VERSION 5.7 ;
  NOWIREEXTENSIONATPIN ON ;
  DIVIDERCHAR "/" ;
  BUSBITCHARS "[]" ;
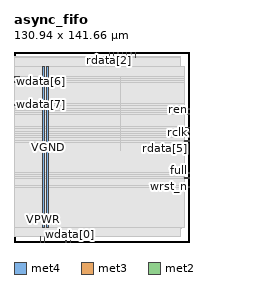
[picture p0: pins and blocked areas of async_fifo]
MACRO async_fifo
  CLASS BLOCK ;
  FOREIGN async_fifo ;
  ORIGIN 0.000 0.000 ;
  SIZE 130.940 BY 141.660 ;
  PIN VGND
    DIRECTION INOUT ;
    USE GROUND ;
    PORT
      LAYER met4 ;
        RECT 24.340 10.640 25.940 130.800 ;
    END
  END VGND
  PIN VPWR
    DIRECTION INOUT ;
    USE POWER ;
    PORT
      LAYER met4 ;
        RECT 21.040 10.640 22.640 130.800 ;
    END
  END VPWR
  PIN empty
    DIRECTION OUTPUT ;
    USE SIGNAL ;
    ANTENNADIFFAREA 0.340600 ;
    PORT
      LAYER met3 ;
        RECT 126.940 95.240 130.940 95.840 ;
    END
  END empty
  PIN full
    DIRECTION OUTPUT ;
    USE SIGNAL ;
    ANTENNADIFFAREA 0.340600 ;
    PORT
      LAYER met3 ;
        RECT 126.940 47.640 130.940 48.240 ;
    END
  END full
  PIN rclk
    DIRECTION INPUT ;
    USE SIGNAL ;
    ANTENNAGATEAREA 0.852000 ;
    PORT
      LAYER met3 ;
        RECT 126.940 81.640 130.940 82.240 ;
    END
  END rclk
  PIN rdata[0]
    DIRECTION OUTPUT ;
    USE SIGNAL ;
    ANTENNADIFFAREA 0.340600 ;
    PORT
      LAYER met3 ;
        RECT 126.940 78.240 130.940 78.840 ;
    END
  END rdata[0]
  PIN rdata[1]
    DIRECTION OUTPUT ;
    USE SIGNAL ;
    ANTENNADIFFAREA 0.340600 ;
    PORT
      LAYER met2 ;
        RECT 87.030 137.660 87.310 141.660 ;
    END
  END rdata[1]
  PIN rdata[2]
    DIRECTION OUTPUT ;
    USE SIGNAL ;
    ANTENNADIFFAREA 0.340600 ;
    PORT
      LAYER met2 ;
        RECT 70.930 137.660 71.210 141.660 ;
    END
  END rdata[2]
  PIN rdata[3]
    DIRECTION OUTPUT ;
    USE SIGNAL ;
    ANTENNADIFFAREA 0.340600 ;
    PORT
      LAYER met2 ;
        RECT 74.150 137.660 74.430 141.660 ;
    END
  END rdata[3]
  PIN rdata[4]
    DIRECTION OUTPUT ;
    USE SIGNAL ;
    ANTENNADIFFAREA 0.340600 ;
    PORT
      LAYER met2 ;
        RECT 80.590 137.660 80.870 141.660 ;
    END
  END rdata[4]
  PIN rdata[5]
    DIRECTION OUTPUT ;
    USE SIGNAL ;
    ANTENNADIFFAREA 0.340600 ;
    PORT
      LAYER met3 ;
        RECT 126.940 74.840 130.940 75.440 ;
    END
  END rdata[5]
  PIN rdata[6]
    DIRECTION OUTPUT ;
    USE SIGNAL ;
    ANTENNADIFFAREA 0.340600 ;
    PORT
      LAYER met2 ;
        RECT 83.810 137.660 84.090 141.660 ;
    END
  END rdata[6]
  PIN rdata[7]
    DIRECTION OUTPUT ;
    USE SIGNAL ;
    ANTENNADIFFAREA 0.340600 ;
    PORT
      LAYER met2 ;
        RECT 77.370 137.660 77.650 141.660 ;
    END
  END rdata[7]
  PIN ren
    DIRECTION INPUT ;
    USE SIGNAL ;
    ANTENNAGATEAREA 0.196500 ;
    PORT
      LAYER met3 ;
        RECT 126.940 98.640 130.940 99.240 ;
    END
  END ren
  PIN rrst_n
    DIRECTION INPUT ;
    USE SIGNAL ;
    ANTENNAGATEAREA 0.426000 ;
    PORT
      LAYER met3 ;
        RECT 126.940 85.040 130.940 85.640 ;
    END
  END rrst_n
  PIN wclk
    DIRECTION INPUT ;
    USE SIGNAL ;
    ANTENNAGATEAREA 0.852000 ;
    PORT
      LAYER met3 ;
        RECT 0.000 122.440 4.000 123.040 ;
    END
  END wclk
  PIN wdata[0]
    DIRECTION INPUT ;
    USE SIGNAL ;
    ANTENNAGATEAREA 0.213000 ;
    PORT
      LAYER met2 ;
        RECT 41.950 0.000 42.230 4.000 ;
    END
  END wdata[0]
  PIN wdata[1]
    DIRECTION INPUT ;
    USE SIGNAL ;
    ANTENNAGATEAREA 0.213000 ;
    PORT
      LAYER met2 ;
        RECT 90.250 137.660 90.530 141.660 ;
    END
  END wdata[1]
  PIN wdata[2]
    DIRECTION INPUT ;
    USE SIGNAL ;
    ANTENNAGATEAREA 0.213000 ;
    PORT
      LAYER met2 ;
        RECT 22.630 0.000 22.910 4.000 ;
    END
  END wdata[2]
  PIN wdata[3]
    DIRECTION INPUT ;
    USE SIGNAL ;
    ANTENNAGATEAREA 0.213000 ;
    PORT
      LAYER met2 ;
        RECT 61.270 137.660 61.550 141.660 ;
    END
  END wdata[3]
  PIN wdata[4]
    DIRECTION INPUT ;
    USE SIGNAL ;
    ANTENNAGATEAREA 0.213000 ;
    PORT
      LAYER met2 ;
        RECT 38.730 0.000 39.010 4.000 ;
    END
  END wdata[4]
  PIN wdata[5]
    DIRECTION INPUT ;
    USE SIGNAL ;
    ANTENNAGATEAREA 0.213000 ;
    PORT
      LAYER met2 ;
        RECT 19.410 0.000 19.690 4.000 ;
    END
  END wdata[5]
  PIN wdata[6]
    DIRECTION INPUT ;
    USE SIGNAL ;
    ANTENNAGATEAREA 0.213000 ;
    PORT
      LAYER met3 ;
        RECT 0.000 119.040 4.000 119.640 ;
    END
  END wdata[6]
  PIN wdata[7]
    DIRECTION INPUT ;
    USE SIGNAL ;
    ANTENNAGATEAREA 0.213000 ;
    PORT
      LAYER met3 ;
        RECT 0.000 102.040 4.000 102.640 ;
    END
  END wdata[7]
  PIN wen
    DIRECTION INPUT ;
    USE SIGNAL ;
    ANTENNAGATEAREA 0.196500 ;
    PORT
      LAYER met3 ;
        RECT 126.940 51.040 130.940 51.640 ;
    END
  END wen
  PIN wrst_n
    DIRECTION INPUT ;
    USE SIGNAL ;
    ANTENNAGATEAREA 0.426000 ;
    PORT
      LAYER met3 ;
        RECT 126.940 40.840 130.940 41.440 ;
    END
  END wrst_n
  OBS
      LAYER nwell ;
        RECT 5.330 10.795 125.310 130.645 ;
      LAYER li1 ;
        RECT 5.520 10.795 125.120 130.645 ;
      LAYER met1 ;
        RECT 0.530 10.240 125.120 130.800 ;
      LAYER met2 ;
        RECT 0.550 137.380 60.990 138.450 ;
        RECT 61.830 137.380 70.650 138.450 ;
        RECT 71.490 137.380 73.870 138.450 ;
        RECT 74.710 137.380 77.090 138.450 ;
        RECT 77.930 137.380 80.310 138.450 ;
        RECT 81.150 137.380 83.530 138.450 ;
        RECT 84.370 137.380 86.750 138.450 ;
        RECT 87.590 137.380 89.970 138.450 ;
        RECT 90.810 137.380 124.110 138.450 ;
        RECT 0.550 4.280 124.110 137.380 ;
        RECT 0.550 4.000 19.130 4.280 ;
        RECT 19.970 4.000 22.350 4.280 ;
        RECT 23.190 4.000 38.450 4.280 ;
        RECT 39.290 4.000 41.670 4.280 ;
        RECT 42.510 4.000 124.110 4.280 ;
      LAYER met3 ;
        RECT 0.525 123.440 126.940 130.725 ;
        RECT 4.400 122.040 126.940 123.440 ;
        RECT 0.525 120.040 126.940 122.040 ;
        RECT 4.400 118.640 126.940 120.040 ;
        RECT 0.525 103.040 126.940 118.640 ;
        RECT 4.400 101.640 126.940 103.040 ;
        RECT 0.525 99.640 126.940 101.640 ;
        RECT 0.525 98.240 126.540 99.640 ;
        RECT 0.525 96.240 126.940 98.240 ;
        RECT 0.525 94.840 126.540 96.240 ;
        RECT 0.525 86.040 126.940 94.840 ;
        RECT 0.525 84.640 126.540 86.040 ;
        RECT 0.525 82.640 126.940 84.640 ;
        RECT 0.525 81.240 126.540 82.640 ;
        RECT 0.525 79.240 126.940 81.240 ;
        RECT 0.525 77.840 126.540 79.240 ;
        RECT 0.525 75.840 126.940 77.840 ;
        RECT 0.525 74.440 126.540 75.840 ;
        RECT 0.525 52.040 126.940 74.440 ;
        RECT 0.525 50.640 126.540 52.040 ;
        RECT 0.525 48.640 126.940 50.640 ;
        RECT 0.525 47.240 126.540 48.640 ;
        RECT 0.525 41.840 126.940 47.240 ;
        RECT 0.525 40.440 126.540 41.840 ;
        RECT 0.525 10.715 126.940 40.440 ;
      LAYER met4 ;
        RECT 79.415 68.175 79.745 123.585 ;
  END
END async_fifo
END LIBRARY

